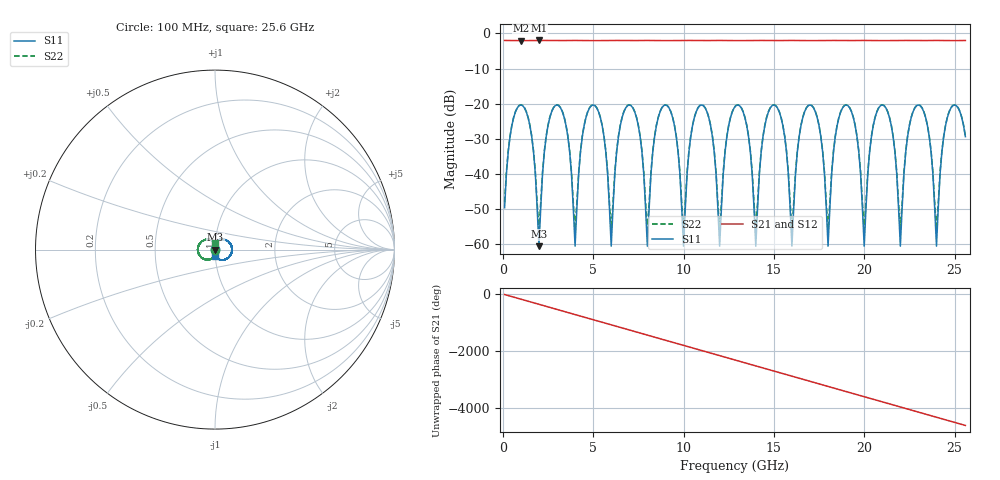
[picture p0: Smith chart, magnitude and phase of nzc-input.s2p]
! scikit-rf 1.8.0 golden reference; NZC forced split impedance 50 ohm
# Hz S RI R 50
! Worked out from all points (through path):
!   256 points, 100 MHz to 25.6 GHz, reference 50 ohm
!   highest |S21| = -2.00 dB at 2 GHz (marker M1); lowest = -2.1 dB at 1 GHz (marker M2)
!   group delay of S21, straight-line fit = 500 ps
!   lowest |S11| = -60.5 dB at 2 GHz (marker M3), VSWR 1.00, Z = 50.1 + j5.6e-16 ohm
!   |S11| at or under -10 dB: start of sweep to end of sweep
!   |S22| runs from -55.9 to -20.3 dB; largest |S21 - S12| = 2.2e-16
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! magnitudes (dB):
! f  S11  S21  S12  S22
! 100 MHz  -49.6  -2.0  -2.0  -48.0
! 1 GHz  -20.4  -2.1  -2.1  -20.3
! 2 GHz  -60.5  -2.0  -2.0  -55.9
! 4.4 GHz  -29.4  -2.0  -2.0  -29.2
! 6 GHz  -60.5  -2.0  -2.0  -55.9
! 7.2 GHz  -21.2  -2.0  -2.0  -21.1
! 8 GHz  -60.5  -2.0  -2.0  -55.9
! 8.6 GHz  -24.0  -2.0  -2.0  -23.9
! 10 GHz  -60.5  -2.0  -2.0  -55.9
! 11.2 GHz  -21.2  -2.0  -2.0  -21.1
! 12 GHz  -60.5  -2.0  -2.0  -55.9
! 12.9 GHz  -20.6  -2.1  -2.1  -20.5
! 14 GHz  -60.5  -2.0  -2.0  -55.9
! 17.1 GHz  -20.6  -2.1  -2.1  -20.5
! 18 GHz  -60.5  -2.0  -2.0  -55.9
! 18.8 GHz  -21.2  -2.0  -2.0  -21.1
! 20 GHz  -60.5  -2.0  -2.0  -55.9
! 21.4 GHz  -24.0  -2.0  -2.0  -23.9
! 22 GHz  -60.5  -2.0  -2.0  -55.9
! 22.8 GHz  -21.2  -2.0  -2.0  -21.1
! 24 GHz  -60.5  -2.0  -2.0  -55.9
! 25.6 GHz  -29.4  -2.0  -2.0  -29.2
